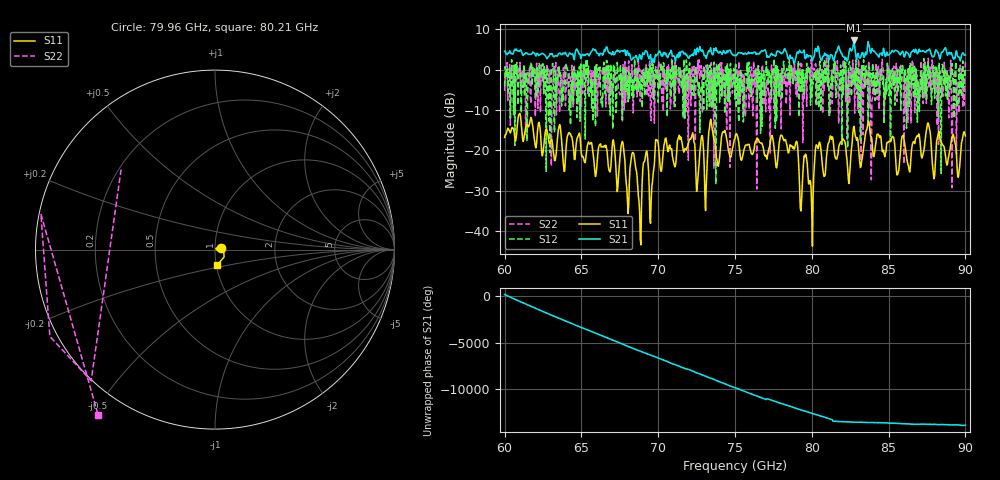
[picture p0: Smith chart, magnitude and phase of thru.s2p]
!Created with skrf (http://scikit-rf.org).
# GHz S RI R 50.0
!freq ReS11 ImS11 ReS21 ImS21 ReS12 ImS12 ReS22 ImS22
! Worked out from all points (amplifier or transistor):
!   721 points, 60 GHz to 90 GHz, reference 50 ohm
!   highest |S21| = 7.2 dB at 82.75 GHz (marker M1)
!   |S21| within 3 dB of that: 86.92 GHz to 87.74 GHz (821.3 MHz wide, 0.94 % of centre) (the widest 1 of 51)
!   unconditionally stable (mu >= 1): 60.35422 GHz to 60.39705 GHz; 60.64337 GHz to 60.69113 GHz; 82.28557 GHz to 82.35917 GHz (the widest 3 of 21)
!   at 65 GHz: K = 0.95, MSG = 3.5 dB, |S12| = -3.9 dB
!   at 75 GHz: K = 0.43, MSG = 5.4 dB, |S12| = -7.3 dB
!   at 90 GHz: K = 0.61, MSG = 2.1 dB, |S12| = -0.6 dB
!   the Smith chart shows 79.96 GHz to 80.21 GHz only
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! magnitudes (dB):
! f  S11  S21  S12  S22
! 60 GHz  -16.8  4.5  -4.1  -5.3
! 65 GHz  -20.9  3.1  -3.9  -9.2
! 67.67 GHz  -17.8  4.6  -12.4  -12.9
! 68 GHz  -32.4  4.6  -2.5  -1.2
! 68.38 GHz  -20.5  3.0  -6.9  -10.7
! 68.79 GHz  -35.2  3.7  -3.0  0.1
! 69.12 GHz  -22.6  4.2  -6.5  -1.1
! 69.54 GHz  -32.3  2.5  -1.2  -12.6
! 70 GHz  -18.2  4.0  -8.1  0.5
! 73.08 GHz  -34.9  3.4  -2.1  0.3
! 74.17 GHz  -15.8  3.8  -4.0  -6.8
! 74.54 GHz  -19.3  4.3  -7.8  -5.3
! 75 GHz  -17.0  3.6  -7.3  -0.3
! 78.96 GHz  -18.1  2.9  -0.4  -6.0
! 80 GHz  -35.5  2.8  -6.8  1.5
! 80.38 GHz  -19.0  4.9  -0.2  0.2
! 82.42 GHz  -28.2  4.1  1.6  -0.4
! 82.75 GHz  -14.0  7.2  -2.6  0.2
! 83.88 GHz  -16.7  4.6  -2.6  -27.2
! 85 GHz  -17.8  3.7  -0.7  -2.8
! 86.12 GHz  -20.3  4.4  -3.5  -6.7
! 90 GHz  -16.4  3.6  -0.6  1.8
